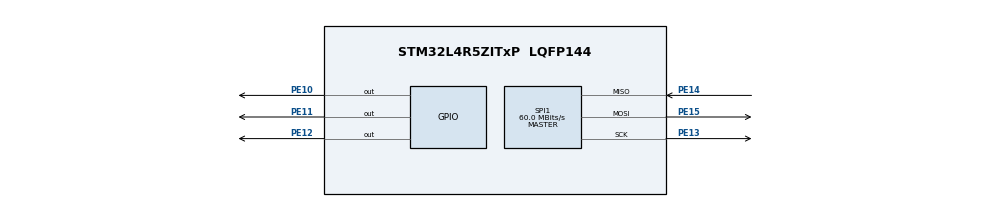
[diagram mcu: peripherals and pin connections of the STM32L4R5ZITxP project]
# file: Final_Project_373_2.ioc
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Mcu.Family=STM32L4
Mcu.Name=STM32L4R5ZITxP
Mcu.Package=LQFP144
NVIC.PriorityGroup=NVIC_PRIORITYGROUP_4
PA0.Signal=S_TIM2_CH1
PA1.Signal=ADCx_IN6
PA10.Signal=USB_OTG_FS_ID
PA13\ (JTMS/SWDIO).Signal=SYS_JTMS-SWDIO
PA14\ (JTCK/SWCLK).Signal=SYS_JTCK-SWCLK
PA3.Signal=ADCx_IN8
PA8.Signal=USB_OTG_FS_SOF
PA9.Signal=USB_OTG_FS_VBUS
PB0.Signal=S_TIM3_CH3
PB1.Signal=ADCx_IN16
PB10.Signal=S_TIM2_CH3
PB12.Signal=SAI2_FS_A
PB13.Signal=SAI2_SCK_A
PB14.Signal=S_TIM15_CH1
PB15.Signal=SAI2_SD_A
PB2.Signal=COMP1_INP
PB3\ (JTDO/TRACESWO).Signal=SPI3_SCK
PB4\ (NJTRST).Signal=SPI3_MISO
PB5.Signal=SPI3_MOSI
PB6.Signal=COMP2_INP
PB8.Signal=I2C1_SCL
PB9.Signal=I2C1_SDA
PC0.Signal=ADCx_IN1
PC1.Signal=ADCx_IN2
PC10.Signal=SDMMC1_D2
PC11.Signal=SDMMC1_D3
PC12.Signal=SDMMC1_CK
PC13.Signal=SYS_WKUP2
PC14-OSC32_IN\ (PC14).Signal=RCC_OSC32_IN
PC15-OSC32_OUT\ (PC15).Signal=RCC_OSC32_OUT
PC2.Signal=ADCx_IN3
PC3.Signal=ADCx_IN4
PC4.Signal=ADCx_IN13
PC5.Signal=ADCx_IN14
PC6.Signal=SAI2_MCLK_A
PC7.Signal=S_TIM3_CH2
PC8.Signal=SDMMC1_D0
PC9.Signal=SDMMC1_D1
PD0.Signal=CAN1_RX
PD14.Signal=S_TIM4_CH3
PD15.Signal=S_TIM4_CH4
PD2.Signal=SDMMC1_CMD
PD3.Signal=USART2_CTS
PD4.Signal=USART2_RTS
PD5.Signal=USART2_TX
PD6.Signal=USART2_RX
PD8.Signal=USART3_TX
PD9.Signal=USART3_RX
PE0.Signal=S_TIM4_ETR
PE10.Signal=GPIO_Output
PE11.Signal=GPIO_Output
PE12.Signal=GPIO_Output
PE13.Mode=Full_Duplex_Master
PE13.Signal=SPI1_SCK
PE14.Mode=Full_Duplex_Master
PE14.Signal=SPI1_MISO
PE15.Mode=Full_Duplex_Master
PE15.Signal=SPI1_MOSI
PE2.Signal=SAI1_MCLK_A
PE3.Signal=SAI1_SD_B
PE7.Signal=S_TIM1_ETR
PE8.Signal=TIM1_CH1N
PE9.Signal=S_TIM1_CH1
PF0.Signal=I2C2_SDA
PF1.Signal=I2C2_SCL
PF2.Signal=I2C2_SMBA
PF7.Signal=SAI1_MCLK_B
PG7.Signal=LPUART1_TX
PG8.Signal=LPUART1_RX
PH0-OSC_IN\ (PH0).Signal=RCC_OSC_IN
PH1-OSC_OUT\ (PH1).Signal=RCC_OSC_OUT
ProjectManager.HeapSize=0x200
ProjectManager.StackSize=0x400
ProjectManager.TargetToolchain=STM32CubeIDE
RCC.AHBFreq_Value=120000000
RCC.APB1Freq_Value=120000000
RCC.APB1TimFreq_Value=120000000
RCC.APB2Freq_Value=120000000
RCC.APB2TimFreq_Value=120000000
RCC.CortexFreq_Value=120000000
RCC.HCLKFreq_Value=120000000
RCC.HSE_VALUE=8000000
RCC.HSI48_VALUE=48000000
RCC.HSI_VALUE=16000000
RCC.LSE_VALUE=32768
RCC.MSI_VALUE=4000000
RCC.PLLN=60
RCC.SYSCLKFreq_VALUE=120000000
RCC.SYSCLKSource=RCC_SYSCLKSOURCE_PLLCLK
RCC.VCOOutputFreq_Value=240000000
SH.ADCx_IN1.0=ADC1_IN1
SH.ADCx_IN13.0=ADC1_IN13
SH.ADCx_IN14.0=ADC1_IN14
SH.ADCx_IN16.0=ADC1_IN16
SH.ADCx_IN2.0=ADC1_IN2
SH.ADCx_IN3.0=ADC1_IN3
SH.ADCx_IN4.0=ADC1_IN4
SH.ADCx_IN6.0=ADC1_IN6
SH.ADCx_IN8.0=ADC1_IN8
SH.S_TIM15_CH1.0=TIM15_CH1
SH.S_TIM1_CH1.0=TIM1_CH1
SH.S_TIM1_ETR.0=TIM1_ETR
SH.S_TIM2_CH1.0=TIM2_CH1
SH.S_TIM2_CH3.0=TIM2_CH3
SH.S_TIM3_CH2.0=TIM3_CH2
SH.S_TIM3_CH3.0=TIM3_CH3
SH.S_TIM4_CH3.0=TIM4_CH3
SH.S_TIM4_CH4.0=TIM4_CH4
SH.S_TIM4_ETR.0=TIM4_ETR
SPI1.BaudRatePrescaler=SPI_BAUDRATEPRESCALER_2
SPI1.CalculateBaudRate=60.0 MBits/s
SPI1.Direction=SPI_DIRECTION_2LINES
SPI1.Mode=SPI_MODE_MASTER
SPI1.VirtualType=VM_MASTER
board=NUCLEO-L4R5ZI-P

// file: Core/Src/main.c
/* USER CODE BEGIN Header */
/**
  ******************************************************************************
  * @file           : main.c
  * @brief          : STM32 + ILI9341 LCD with fast 5-0 countdown
  ******************************************************************************
  */
/* USER CODE END Header */

#include "main.h"
#include <stdint.h>

/* USER CODE BEGIN PD */
#define SPI_CS_GPIO    GPIOE
#define SPI_CS_PIN     GPIO_PIN_12
#define SPI_DC_GPIO    GPIOE
#define SPI_DC_PIN     GPIO_PIN_11
#define SPI_RESET_GPIO GPIOE
#define SPI_RESET_PIN  GPIO_PIN_10

#define CS_LOW()       HAL_GPIO_WritePin(SPI_CS_GPIO, SPI_CS_PIN, GPIO_PIN_RESET)
#define CS_HIGH()      HAL_GPIO_WritePin(SPI_CS_GPIO, SPI_CS_PIN, GPIO_PIN_SET)
#define DC_LOW()       HAL_GPIO_WritePin(SPI_DC_GPIO, SPI_DC_PIN, GPIO_PIN_RESET)
#define DC_HIGH()      HAL_GPIO_WritePin(SPI_DC_GPIO, SPI_DC_PIN, GPIO_PIN_SET)
#define RESET_LOW()    HAL_GPIO_WritePin(SPI_RESET_GPIO, SPI_RESET_PIN, GPIO_PIN_RESET)
#define RESET_HIGH()   HAL_GPIO_WritePin(SPI_RESET_GPIO, SPI_RESET_PIN, GPIO_PIN_SET)

#define WIDTH  240
#define HEIGHT 320

SPI_HandleTypeDef hspi1;
uint8_t RGB_MODE = 0x55; // 16-bit color (RGB565)
uint16_t frame[WIDTH*HEIGHT]; // Full screen buffer

/* USER CODE END PD */

/* USER CODE BEGIN 0 */
void WriteCommand(uint8_t cmd){
    DC_LOW();
    CS_LOW();
    HAL_SPI_Transmit(&hspi1, &cmd, 1, HAL_MAX_DELAY);
    CS_HIGH();
}

void WriteData(uint8_t *data, uint16_t size){
    DC_HIGH();
    CS_LOW();
    HAL_SPI_Transmit(&hspi1, data, size, HAL_MAX_DELAY);
    CS_HIGH();
}

void ILI9341_Reset(void){
    RESET_LOW();
    HAL_Delay(1000);
    RESET_HIGH();
    HAL_Delay(1000);
}

// Fill the frame buffer
void FillFrame(uint16_t color){
    for(uint32_t i=0;i<WIDTH*HEIGHT;i++) frame[i] = color;
}

// Send the frame buffer to the display
void ILI9341_DisplayFrame(void){
    // Column address: 0 → WIDTH-1
    WriteCommand(0x2A);
    uint8_t col[4] = {0x00, 0x00, (WIDTH-1)>>8, (WIDTH-1)&0xFF};
    WriteData(col, 4);

    // Page address: 0 → HEIGHT-1
    WriteCommand(0x2B);
    uint8_t page[4] = {0x00, 0x00, (HEIGHT-1)>>8, (HEIGHT-1)&0xFF};
    WriteData(page, 4);

    // Memory write
    WriteCommand(0x2C);
    DC_HIGH();
    CS_LOW();

    // Send row by row to ensure correct orientation
    for(uint16_t y=0; y<HEIGHT; y++){
        HAL_SPI_Transmit(&hspi1, (uint8_t*)&frame[y*WIDTH], WIDTH*2, HAL_MAX_DELAY);
    }

    CS_HIGH();
}

// 8x8 font for digits 0-9
const uint8_t font_digits[10][8] = {
    {0x3C,0x66,0x6E,0x7E,0x76,0x66,0x3C,0x00}, //0
    {0x18,0x38,0x18,0x18,0x18,0x18,0x3C,0x00}, //1
    {0x3C,0x66,0x06,0x0C,0x18,0x30,0x7E,0x00}, //2
    {0x3C,0x66,0x06,0x1C,0x06,0x66,0x3C,0x00}, //3
    {0x0C,0x1C,0x3C,0x6C,0x7E,0x0C,0x0C,0x00}, //4
    {0x7E,0x60,0x7C,0x06,0x06,0x66,0x3C,0x00}, //5
    {0x1C,0x30,0x60,0x7C,0x66,0x66,0x3C,0x00}, //6
    {0x7E,0x66,0x0C,0x18,0x18,0x18,0x18,0x00}, //7
    {0x3C,0x66,0x66,0x3C,0x66,0x66,0x3C,0x00}, //8
    {0x3C,0x66,0x66,0x3E,0x06,0x0C,0x38,0x00}  //9
};

// Draw digit into frame buffer (fast)
void DrawDigitToFrame(int x,int y,uint8_t digit,uint16_t color,uint8_t scale){
    if(digit>9) return;
    for(uint8_t row=0; row<8; row++){
    	for(uint8_t col=0; col<8; col++){
    	    if(font_digits[digit][row] & (1 << col)){  // <--- use LSB first
    	        for(uint8_t i=0;i<scale;i++){
    	            for(uint8_t j=0;j<scale;j++){
    	                int px = x + col*scale + i;
    	                int py = y + row*scale + j;
    	                if(px<WIDTH && py<HEIGHT) frame[py*WIDTH + px] = color;
    	            }
    	        }
    	    }
    	}
    }
}
/* USER CODE END 0 */

void SystemClock_Config(void);
static void MX_GPIO_Init(void);
static void MX_SPI1_Init(void);

int main(void){
    HAL_Init();
    SystemClock_Config();
    MX_GPIO_Init();
    MX_SPI1_Init();

    HAL_Delay(1000); // Sleep out
    ILI9341_Reset();
    HAL_Delay(1000); // Sleep out
    WriteCommand(0x11);
    HAL_Delay(120); // Sleep out
    WriteCommand(0x3A);
    WriteData(&RGB_MODE,1); // Pixel format
    WriteCommand(0x29);
    HAL_Delay(20); // Display on

    uint16_t bg_colors[6]={0x0000,0x001F,0x07E0,0xFFE0,0x07FF,0xF81F}; // black, blue, green, yellow, cyan, magenta

    while(1){
        for(int i=5;i>=0;i--){
            FillFrame(bg_colors[i]);                  // Fill background
            DrawDigitToFrame((WIDTH-8*20)/2, (HEIGHT-8*20)/2, i, 0xF800, 20);
            ILI9341_DisplayFrame();                   // Display entire frame
            HAL_Delay(500);                           // 0.5s per step
        }
    }
}

/* System Clock Configuration */
void SystemClock_Config(void){
    RCC_OscInitTypeDef RCC_OscInitStruct = {0};
    RCC_ClkInitTypeDef RCC_ClkInitStruct = {0};
    if(HAL_PWREx_ControlVoltageScaling(PWR_REGULATOR_VOLTAGE_SCALE1) != HAL_OK) Error_Handler();
    RCC_OscInitStruct.OscillatorType = RCC_OSCILLATORTYPE_MSI;
    RCC_OscInitStruct.MSIState = RCC_MSI_ON;
    RCC_OscInitStruct.MSICalibrationValue = 0;
    RCC_OscInitStruct.MSIClockRange = RCC_MSIRANGE_6;
    RCC_OscInitStruct.PLL.PLLState = RCC_PLL_NONE;
    if(HAL_RCC_OscConfig(&RCC_OscInitStruct) != HAL_OK) Error_Handler();
    RCC_ClkInitStruct.ClockType = RCC_CLOCKTYPE_HCLK|RCC_CLOCKTYPE_SYSCLK
                                |RCC_CLOCKTYPE_PCLK1|RCC_CLOCKTYPE_PCLK2;
    RCC_ClkInitStruct.SYSCLKSource = RCC_SYSCLKSOURCE_MSI;
    RCC_ClkInitStruct.AHBCLKDivider = RCC_SYSCLK_DIV1;
    RCC_ClkInitStruct.APB1CLKDivider = RCC_HCLK_DIV1;
    RCC_ClkInitStruct.APB2CLKDivider = RCC_HCLK_DIV1;
    if(HAL_RCC_ClockConfig(&RCC_ClkInitStruct, FLASH_LATENCY_0) != HAL_OK) Error_Handler();
}

/* SPI1 init */
static void MX_SPI1_Init(void){
    hspi1.Instance = SPI1;
    hspi1.Init.Mode = SPI_MODE_MASTER;
    hspi1.Init.Direction = SPI_DIRECTION_2LINES;
    hspi1.Init.DataSize = SPI_DATASIZE_8BIT;
    hspi1.Init.CLKPolarity = SPI_POLARITY_LOW;
    hspi1.Init.CLKPhase = SPI_PHASE_1EDGE;
    hspi1.Init.NSS = SPI_NSS_SOFT;
    hspi1.Init.BaudRatePrescaler = SPI_BAUDRATEPRESCALER_2;
    hspi1.Init.FirstBit = SPI_FIRSTBIT_MSB;
    hspi1.Init.TIMode = SPI_TIMODE_DISABLE;
    hspi1.Init.CRCCalculation = SPI_CRCCALCULATION_DISABLE;
    hspi1.Init.CRCPolynomial = 7;
    if(HAL_SPI_Init(&hspi1) != HAL_OK) Error_Handler();
}

/* GPIO init */
static void MX_GPIO_Init(void){
    GPIO_InitTypeDef GPIO_InitStruct = {0};
    __HAL_RCC_GPIOE_CLK_ENABLE();
    GPIO_InitStruct.Pin = SPI_CS_PIN|SPI_DC_PIN|SPI_RESET_PIN;
    GPIO_InitStruct.Mode = GPIO_MODE_OUTPUT_PP;
    GPIO_InitStruct.Pull = GPIO_NOPULL;
    GPIO_InitStruct.Speed = GPIO_SPEED_FREQ_LOW;
    HAL_GPIO_Init(GPIOE, &GPIO_InitStruct);
}

/* Error Handler */
void Error_Handler(void){
    __disable_irq();
    while(1){}
}
